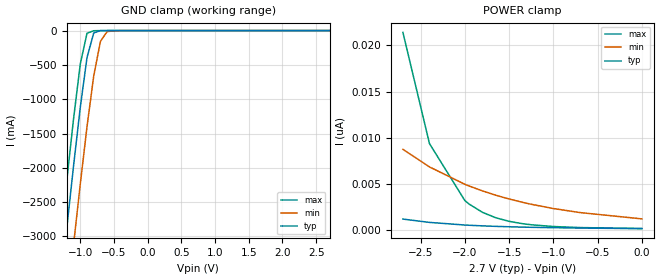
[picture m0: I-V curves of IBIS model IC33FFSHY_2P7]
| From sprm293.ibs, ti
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|   Model IC33FFSHY_2P7
[Model]   IC33FFSHY_2P7
Model_type   Input
Polarity   Non-Inverting
Vinl =   0.8100V
Vinh =   1.8900V
C_comp   2.1398pF   2.1767pF   2.1317pF
[Temperature Range]   25.0000   0.1250k   -40.0000
[Voltage Range]   2.7000V   2.5000V   3.0000V
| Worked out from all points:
|   GND clamp passes 1 mA (typ) near -0.69 V on its own axis
[GND_clamp]
| voltage   I(typ)   I(min)   I(max)
-2.7V     -17.42A    -18.52A    -16.77A
-1.3V     -3.808A    -4.968A    -3.114A
-1.2V     -2.88A     -4.039A    -2.185A
-1.1V     -1.977A    -3.127A    -1.292A
-1V       -1.123A    -2.241A    -489.8mA
-900mV    -393.5mA   -1.402A    -39.28mA
-800mV    -34.06mA   -660.7mA   -2.403mA
-700mV    -1.064mA   -156.4mA   -232.2uA
-600mV    -42.88uA   -13.11mA   -13.27uA
-400mV    -95.51nA   -45.69uA   -11.76nA
2.7V      157.4pA    1.382nA    146.5pA
[POWER_clamp]
| voltage   I(typ)   I(min)   I(max)
-2.7V     1.196nA    8.75nA     21.41nA
-2.4V     835.6pA    6.844nA    9.375nA
-2V       550.3pA    4.964nA    3.201nA
-1.95V    524.9pA    4.772nA    2.81nA
-1.8V     459pA      4.243nA    1.92nA
-1.65V    405.4pA    3.778nA    1.335nA
-1.5V     361.8pA    3.37nA     951pA
-1.35V    325.5pA    3.012nA    697.5pA
-1.25V    304.8pA    2.798nA    578.3pA
-1V       262.5pA    2.338nA    389.3pA
-700mV    223.9pA    1.901nA    276.4pA
0V        157.4pA    1.218nA    172.4pA
